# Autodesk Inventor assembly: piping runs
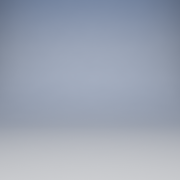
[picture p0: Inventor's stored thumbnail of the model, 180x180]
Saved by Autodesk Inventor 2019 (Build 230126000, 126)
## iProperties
ActiveState: False
BendRadius: UnInitValue
CouplingKey: v3#771d4942-b9e7-43bc-9d41-ab12a9580492#3
DefaultBendRadius: UnInitValue
Diameter: 1/2
DiameterType: Nominal
Elbow45Key: v3#626cc28c-1a24-4045-be0d-40d896dc828d#3
Elbow90Key: v3#bc6b44ab-9235-4590-b699-74498030a1ff#3
ElbowCustomKey: UnInitValue
EndFittingKey: UnInitValue
Ending: UnInitValue
FittingMaterial: UnInitValue
FittingStandard: UnInitValue
FlangeKey: UnInitValue
Gap: UnInitValue
GasketKey: UnInitValue
ID: UnInitValue
IntermediateSegmentsInc: 2,540 mm
IntermediateSegmentsMax: 5080,000 mm
IntermediateSegmentsMin: 50,800 mm
IsButtWelded: False
IsFlanged: False
IsSelfDraining: False
Material: UnInitValue
MixedUnits: False
Name: ANSI/ASME B36.19M-ASME B16.3 - Potrubí se závity a litinovými tvarovkami
OD: UnInitValue
PipeKey: v3#323c0148-c750-449d-a0c6-11721f2a5046#1
PipeType: Rigid Pipe
PipingComponentColor: As Material
RoundUpValue: UnInitValue
RouteDirection45: True
RouteDirection90: True
Schedule: 40S
ShowGap: UnInitValue
Standard: UnInitValue
StartFittingKey: UnInitValue
SuppressEndFitting: UnInitValue
SuppressStartFitting: UnInitValue
TerminationSegmentsInc: 2,540 mm
TerminationSegmentsMax: 5080,000 mm
TerminationSegmentsMin: 50,800 mm
UseFlangsForCouplings: UnInitValue
UseSubASM: UnInitValue
_ComponentInfo: <CS><C N="Pipe" R="1.066800" IR="0.789940" PL="PL" PN="ANSI/ASME B36.19M Pipe with Threaded Ends 1/2 - Schedule 40S"><CO N="1"><FE V="0"/><FD V="1"/><ET V="Thre
Angle: 92,00 deg
CouplingKey: UnInitValue
Diameter: 1
Elbow45Key: v3#bf26aa2a-f3dd-474c-8758-922a145c2b02#15
Elbow90Key: v3#3e93288f-9bb7-4e46-9d6b-544f8c20ca1c#3
ElbowCustomKey: v3#1f3bd44a-47ab-42f9-b3e0-74afa0c3f0ca#3
Gap: 2,388 mm
IntermediateSegmentsInc: 0.00001 in
IsButtWelded: True
IsSelfDraining: True
Name: ASME BPE - Ocelová trubka svařovaná na tupo/
PipeKey: v3#b10c956f-6fc6-429e-8056-0864a8581764#35
Schedule: ID=0.87
ShowGap: True
TerminationSegmentsInc: 0.00001 in
_ComponentInfo: <CS><C N="Pipe" R="1.270000" OR="1.270000" IR="1.104900" PL="PL" PartType="pipe" SymKey="" PN="ASTM A 269 Tube with Welded ends 1 x 0.87"><CO N="1"><FE V="2"/><
Angle: UnInitValue
BendRadius: 12,700 mm
Elbow45Key: UnInitValue
Elbow90Key: UnInitValue
EndFittingKey: v3#c5e461f5-5e73-4f2e-8c1e-4358d4d6f46c#4
ID: 1,27
IntermediateSegmentsInc: UnInitValue
IntermediateSegmentsMax: UnInitValue
IntermediateSegmentsMin: UnInitValue
IsButtWelded: UnInitValue
IsFlanged: UnInitValue
IsSelfDraining: UnInitValue
MixedUnits: UnInitValue
Name: Hydraulická hadice - s vnitřním závitem - otočné
OD: 2,2352
PipeKey: v3#d489867e-ac9b-47ea-b952-0a1b885f66be#4
PipeType: Flexible Hose
RoundUpValue: 3,175 mm
RouteDirection45: UnInitValue
RouteDirection90: UnInitValue
Schedule: ID=0.5
StartFittingKey: v3#c5e461f5-5e73-4f2e-8c1e-4358d4d6f46c#4
SuppressEndFitting: False
SuppressStartFitting: False
TerminationSegmentsInc: UnInitValue
TerminationSegmentsMax: UnInitValue
TerminationSegmentsMin: UnInitValue
UseSubASM: True
_ComponentInfo: <CS><C N="Pipe" R="1.117600" OR="1.117600" IR="0.635000" PL="PL" PartType="" SymKey="" PN="Parker Hydraulic Hose - No Skive 1/2"><CO N="1"><FE V="0"/><FD V="0"/
CouplingKey: v3#ed415c76-4cec-44a3-ba67-72e47bf70384#4
Elbow45Key: v3#2e5fd082-3851-4eb0-bde1-6c7078a7d72b#4
Elbow90Key: v3#82a08401-12d7-413b-b7f9-9cf3b607be7b#4
IntermediateSegmentsMin: 25,400 mm
Name: ASTM A53/A53M-ASME B16.11 - Ocelové potrubí svařované
PipeKey: v3#4ce5e9fa-6da0-4801-ac02-ee7a0fb518d6#7
Schedule: 40
TerminationSegmentsMin: 25,400 mm
_ComponentInfo: <CS><C N="Pipe" R="1.066800" IR="0.789940" PL="PL" PN="ASTM A 53/A 53M Pipe 1/2 - Schedule 40"><CO N="1"><FE V="0"/><FD V="0"/><ET V="Welded"/><NS V="1/2"/><MA 
Diameter: M40
Elbow45Key: v3#97879d80-057e-491b-840b-74a9b3a7cf63#17
Elbow90Key: v3#ace818b0-7b7c-4ad9-b19c-6da358a202c1#17
IntermediateSegmentsInc: 1,000 mm
IntermediateSegmentsMax: 5000,000 mm
IntermediateSegmentsMin: 60,000 mm
Name: DIN 2458/DIN 2605 -Ocelové potrubí svařované a tvarovky
PipeKey: v3#dcef2839-8903-4c98-a96c-b861f5d9bb7f#98
Schedule: ID=30.7
TerminationSegmentsInc: 1,000 mm
TerminationSegmentsMax: 5000,000 mm
TerminationSegmentsMin: 60,000 mm
_ComponentInfo: <CS><C N="Pipe" R="2.415000" IR="1.535000" PL="PL" PN="DIN 2458 Pipe 48.3 x 8.8"><CO N="1"><FE V="2"/><FD V="0"/><ET V="Welded"/><NS V="M40"/><MA V="0.000000"/>
EndFittingKey: v3#933069c9-73b6-4141-af99-628d4a97b2c2#1
Name: Hydraulická hadice - SAE přírubové spojky
StartFittingKey: v3#933069c9-73b6-4141-af99-628d4a97b2c2#1
CouplingKey: v3#29993622-4c6a-437e-8b8c-43a0846f8735#1
Elbow45Key: v3#d7b5d569-4a12-4d65-ba55-12203d6ac7ed#1
Elbow90Key: v3#25d2a8db-6517-4627-a5a4-9d27e4d26b9b#1
IntermediateSegmentsMax: 2540,000 mm
Name: ASTM D 1785-ASTM D 2466 -  PVC potrubí spojované a tvarovky
PipeKey: v3#4bf12049-4375-491b-8f13-d4ee0c517c57#1
TerminationSegmentsMax: 2540,000 mm
_ComponentInfo: <CS><C N="Pipe" R="1.066800" IR="0.789940" PL="PL" PN="ASTM D 1785 Pipe 1/2 - Schedule 40"><CO N="1"><FE V="0"/><FD V="0"/><ET V="Jointed"/><NS V="1/2"/><MA V="
CouplingKey: v3#b06656e5-2b55-488c-bcf0-6a90c79c4683#2
Elbow45Key: v3#421a8b99-1721-409a-bc3b-c00889561754#1
Elbow90Key: v3#17490b17-1dd8-40fc-8de7-1a70c3bab2d7#1
Name: ISO 4065-ISO 3633 - PVC potrubí a tvarovky
PipeKey: v3#4f84f716-5ba0-45ef-967a-c32c3d7345ce#70
Schedule: S40
_ComponentInfo: <CS><C N="Pipe" R="2.000000" IR="1.950000" PL="PL" PN="ISO 4065 Pipe 40 x 0.5 S40"><CO N="1"><FE V="0"/><FD V="0"/><ET V="Jointed"/><NS V="M40"/><MA V="6.000000
Elbow45Key: v3#81684a3f-f2a4-4fe6-95b1-f067ddead22f#1
Elbow90Key: v3#451ae64e-c79d-4cba-b533-c09b8090ecb2#1
IntermediateSegmentsInc: 10,000 mm
IntermediateSegmentsMax: 9000,000 mm
IntermediateSegmentsMin: 1000,000 mm
Name: ISO 2531 - Potrubí z tvárné litiny s přírubami a tvarovkami
PipeKey: v3#f52fbdcb-ece8-4303-8b76-5dbe8c7f2f9c#16
Schedule: PN10
TerminationSegmentsInc: 10,000 mm
TerminationSegmentsMax: 9000,000 mm
TerminationSegmentsMin: 1000,000 mm
_ComponentInfo: <CS><C N="Pipe" R="2.700000" IR="2.000000" PL="PL" PN="ISO 2531 Pipe with Integrally Cast Flanges DN40 PN 10"><CO N="1"><FE V="0"/><FD V="0"/><ET V="Flanged"/><
CouplingKey: v3#7e56b2cb-a132-4546-b8a7-a14538454b94#3
Elbow45Key: v3#a96c5204-26e4-4bb2-b8f1-f0623fbc94bb#2
Elbow90Key: v3#b72bb08b-ad33-47cc-a03d-7f3d76c6616b#3
Name: ISO 7598/ISO 49 -  Ocelové potrubí se závity a litinovými tvarovkami
PipeKey: v3#1052637f-74b5-47f4-adeb-d4e8d3fa53b8#1
Schedule: ID=16.1
_ComponentInfo: <CS><C N="Pipe" R="1.065000" IR="0.805000" PL="PL" PN="ISO 7598 Tube with Threaded Ends DN15"><CO N="1"><FE V="0"/><FD V="1"/><ET V="Threaded"/><NS V="1/2"/><MA
CouplingKey: v3#181262db-c004-4877-bc40-c64b931a44f6#3
Elbow45Key: v3#960407aa-00b9-4d72-aae7-d50595845cfd#3
Elbow90Key: v3#6c92b367-65e9-486b-b952-db434ae2548d#3
IntermediateSegmentsMin: 20,000 mm
Name: JIS G 3442/JIS B 2301  Ocelové potrubí se závity a litinové tvarovky
PipeKey: v3#9964fba4-9d5a-4d75-85a8-e38022ccdce1#2
TerminationSegmentsMin: 20,000 mm
_ComponentInfo: <CS><C N="Pipe" R="1.085000" IR="0.805000" PL="PL" PN="JIS G 3442 Pipe with Threaded Ends 21.7 x 2.8"><CO N="1"><FE V="0"/><FD V="1"/><ET V="Threaded"/><NS V="1
Diameter: 6
Elbow90Key: v3#6a678020-d9d9-4685-bba9-906b9a167083#10
FlangeKey: v3#c11442d2-c568-438f-a870-8ac9b5b636cb#10
GasketKey: v3#2a41914c-f5fb-4682-9c6a-1870d826d3d0#23
IntermediateSegmentsMin: 76,200 mm
IsFlanged: True
Name: ASTM A 53/A-ASME B16.5 – Ocelové trubky přírubové závitové
PipeKey: v3#c5bd7d28-cdb3-4507-9f3d-c2787d93fe8a#40
RouteDirection45: False
TerminationSegmentsMin: 76,200 mm
_ComponentInfo: <CS><C N="Elbow90" ER="21.590000" S1="21.590000" S2="21.590000" D1="0.000000" D2="0.000000" PartType="fitting" SymKey="ELFL"><CO N="1"><FE V="2"/><FD V="1"/><ET
EndFittingKey: v3#c8250148-a7b6-458b-b7bd-3b56763ca7cc#13
Name: Hydraulická hadice - s vnějším kuželovým závitem
StartFittingKey: v3#c8250148-a7b6-458b-b7bd-3b56763ca7cc#13
Created: 2006-09
Part Number: piping runs
Document SubType Name: Tube & Pipe
Manufacturer: Standard
Standards Organization: Custom
Material: Všeobecné
Elbow90Key: v3#97ecdcaf-8aa3-4fb0-8b6a-3da783de2ad5#108
Gap: 1,575 mm
Name: ASTM A 53/A-ASME B16.9 – Ocelové trubky svařované na tupo
PipeKey: v3#4ce5e9fa-6da0-4801-ac02-ee7a0fb518d6#77
_ComponentInfo: <CS><C N="Elbow90" ER="15.240000" S1="15.240000" S2="15.240000" D1="0.000000" D2="0.000000" PartType="fitting" SymKey="ELBW"><CO N="1"><FE V="2"/><FD V="0"/><ET
EndFittingKey: v3#b50cb43e-68c0-48ac-8e25-7ef224ce0e6c#3
Name: Hydraulické hadice - s vnějším přímým závitem
StartFittingKey: v3#b50cb43e-68c0-48ac-8e25-7ef224ce0e6c#3
ActiveState: True
CouplingKey: v3#52ad3977-2b89-4007-a6a6-7626bac0ae85#4
Elbow45Key: v3#5c2ab816-abcb-49a6-a106-4733af000f51#4
Elbow90Key: v3#160eac10-3e6f-4b5c-839c-61eee0d373dc#4
Name: ASME B36.10M-ASME B16.11 - Ocelové potrubí se závity
PipeKey: v3#4a736116-503a-44ad-a922-868ac6b46736#1
Schedule: 30
_ComponentInfo: <CS><C N="Pipe" R="1.066800" IR="0.825500" PL="PL" PN="ASME B36.10M Pipe with Threaded Ends 1/2 - Schedule 30"><CO N="1"><FE V="0"/><FD V="1"/><ET V="Threaded"/
Name: Hydraulická hadice - bez tvarovek
SuppressEndFitting: True
SuppressStartFitting: True
EndFittingKey: v3#cc3bd835-95a2-497d-9893-176cd9c426f6#7
Name: Hydraulická hadice - s vnitřním kuželovým závitem
StartFittingKey: v3#cc3bd835-95a2-497d-9893-176cd9c426f6#7
Name: DIN 8062/DIN 8063 - PVC-U potrubí spojované a tvarovky
RoutePreview: Solid
Schedule: 5
IntermediateSegmentsMin: 60.000 mm
IntermediateSegmentsMax: 5000.000 mm
IntermediateSegmentsInc: 1.000 mm
TerminationSegmentsMin: 60.000 mm
TerminationSegmentsMax: 5000.000 mm
TerminationSegmentsInc: 1.000 mm
SolidRoutePreviewColor: 12632064
PipeKey: v3#3d294dc7-89c3-4c37-a0ae-28c15a73bfd0#13
CouplingKey: v3#3edf83e2-464b-4b31-84c5-c329ffbf2a4f#5
Elbow90Key: v3#fbd68fd5-590c-4cb5-8c20-9e9bdd396a04#5
Elbow45Key: v3#2f597a97-b15b-49d4-87cb-7bfe69eb62ee#5
_ComponentInfo: <CS><C N="Pipe" R="2.000000" IR="1.700000" PL="PL" PN="DIN 8062 Pipe 40 x 3"><CO N="1"><FE V="0"/><FD V="0"/><ET V="Jointed"/><NS V="M40"/><MA V="8.000000"/><MI
CouplingKey: v3#0dc1ae02-7bbf-4ccf-8498-581434b0a765#3
DefaultBendRadius: 50,800 mm
IntermediateSegmentsMin: 0,000 mm
Name: ASTM B 88-ASME B16.22 -  Měděné potrubí pájené
PipeKey: v3#44b182c9-4bce-4825-bb4d-596143122252#7
PipeType: Tubing
Schedule: L
TerminationSegmentsMin: 0,000 mm
_ComponentInfo: <CS><C N="Pipe" R="0.793750" IR="0.692150" PL="PL" PN="ASTM B 88 Tube 1/2 - Type L"><CO N="1"><FE V="0"/><FD V="0"/><ET V="Soldered"/><NS V="1/2"/><MA V="2.5400
CouplingKey: v3#eaa8de87-dc67-4eca-ba7e-4267a30f8f7f#2
Elbow45Key: v3#2769403e-a4fd-4a4c-8e4c-659ea845bd78#2
Elbow90Key: v3#c4513a61-3106-4a78-baf9-a1badd100245#2
IntermediateSegmentsMax: 2500,000 mm
Name: JIS K 6741/JIS K 6739 -PVC-U potrubí spojované a tvarovky
PipeKey: v3#45338dd0-af69-48c0-a2ed-8ade33a08701#5
Schedule: VP
TerminationSegmentsMax: 2500,000 mm
_ComponentInfo: <CS><C N="Pipe" R="2.400000" IR="2.040000" PL="PL" PN="JIS K 6741 Pipe VP 40"><CO N="1"><FE V="0"/><FD V="1"/><ET V="Jointed"/><NS V="M40"/><MA V="4.000000"/><M
count: 52
Refkey_Axis1_Context: 2|0|0|0|1|0|0|0|
Refkey_Axis1: 6|0|0|0|44|0|0|0|78|0|65|0|77|0|69|0|83|0|10|0|67|0|111|0|108|0|111|0|114|0|115|0|10|0|49|0|58|0|10|0|10|0|69|0|78|0|68|0|10|0|0|0|
Refkey_Axis2_Context: 2|0|0|0|1|0|0|0|
Refkey_Axis2: 6|0|0|0|88|0|0|0|78|0|65|0|77|0|69|0|83|0|10|0|67|0|111|0|108|0|111|0|114|0|115|0|10|0|49|0|58|0|82|0|111|0|117|0|116|0|101|0|32|0|85|0|73|0|32|0|84|0|111|0|111
Refkey_Axis3_Context: 2|0|0|0|1|0|0|0|
Refkey_Axis3: 6|0|0|0|88|0|0|0|78|0|65|0|77|0|69|0|83|0|10|0|67|0|111|0|108|0|111|0|114|0|115|0|10|0|49|0|58|0|82|0|111|0|117|0|116|0|101|0|32|0|85|0|73|0|32|0|84|0|111|0|111
Refkey_Ext_Context: 2|0|0|0|1|0|0|0|
Refkey_Ext: 6|0|0|0|92|0|0|0|78|0|65|0|77|0|69|0|83|0|10|0|67|0|111|0|108|0|111|0|114|0|115|0|10|0|49|0|58|0|82|0|111|0|117|0|116|0|101|0|32|0|85|0|73|0|32|0|84|0|111|0|111
Refkey_Snap_Context: 2|0|0|0|1|0|0|0|
Refkey_Snap: 6|0|0|0|84|0|0|0|78|0|65|0|77|0|69|0|83|0|10|0|67|0|111|0|108|0|111|0|114|0|115|0|10|0|49|0|58|0|82|0|111|0|117|0|116|0|101|0|32|0|85|0|73|0|32|0|84|0|111|0|111
FlangeKey: v3#24991861-26e3-4c21-a713-f46e314eddd5#10
Name: ASTM A 53/A 53M - Ocelová trubka svařovaná na tupo/přírubová trubka
UseFlangsForCouplings: False
_ComponentInfo: <CS><C N="Pipe" R="8.413750" OR="8.413750" IR="7.702550" PL="PL" PartType="pipe" SymKey="" PN="ASTM A 53/A 53M Pipe 6 - Schedule 40"><CO N="1"><FE V="2"/><FD V=
CouplingKey: v3#12b64993-10e6-4915-8315-0c0cce209ad0#8
Elbow45Key: v3#28e76e79-e22c-40ab-8be2-ff545b1407c5#8
Elbow90Key: v3#1f65ece3-c41a-48d4-8661-909ed34ade86#8
Name: JIS G 3458/JIS B 2316 - Ocelové potrubí svařované a tvarovky
PipeKey: v3#da14b0ab-0b36-4851-8d66-8c9cd0bcbe86#23
Schedule: 80
_ComponentInfo: <CS><C N="Pipe" R="2.430000" IR="1.920000" PL="PL" PN="JIS G 3458 Pipe 40 A x Sch 80"><CO N="1"><FE V="0"/><FD V="1"/><ET V="Welded"/><NS V="M40"/><MA V="0.0000
CouplingKey: v3#d2599e7a-1865-48da-a234-5418a1cd5dfe#3
Elbow45Key: v3#6ce5b1be-37aa-4928-b23a-0df64e6ddf38#2
Elbow90Key: v3#9fba244e-81ed-4fc6-a9ac-7eb372fa3ffe#3
Name: DIN 2458/DIN EN 10242 - Ocelové potrubí se závity a litinové tvarovky
PipeKey: v3#d689fd5f-ac5a-46d7-a883-3089b2f6e0a4#28
Schedule: ID=12.3
_ComponentInfo: <CS><C N="Pipe" R="1.065000" IR="0.615000" PL="PL" PN="DIN 2458 Pipe with Threaded Ends 21.3 x 4.5"><CO N="1"><FE V="0"/><FD V="1"/><ET V="Threaded"/><NS V="1/2
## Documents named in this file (1)
- C:\Users\CSY\Desktop\csy-126\piping runs.iam
